VERSION 5.7 ;
  NOWIREEXTENSIONATPIN ON ;
  DIVIDERCHAR "/" ;
  BUSBITCHARS "[]" ;
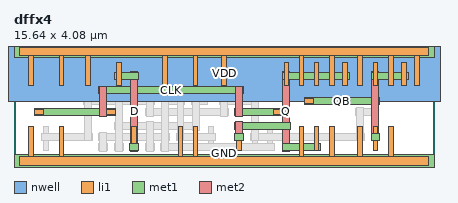
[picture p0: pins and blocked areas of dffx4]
MACRO dffx4
  CLASS BLOCK ;
  FOREIGN dffx4 ;
  ORIGIN 0.000 0.000 ;
  SIZE 15.640 BY 4.080 ;
  PIN VDD
    ANTENNADIFFAREA 7.371200 ;
    PORT
      LAYER nwell ;
        RECT -0.230 2.200 15.870 4.410 ;
      LAYER li1 ;
        RECT 0.210 3.915 15.430 4.245 ;
        RECT 0.545 2.800 0.715 3.915 ;
        RECT 1.685 2.800 1.855 3.915 ;
        RECT 2.665 2.800 2.835 3.915 ;
        RECT 5.545 2.800 5.715 3.915 ;
        RECT 6.675 2.800 6.845 3.915 ;
        RECT 7.735 2.800 7.905 3.915 ;
        RECT 10.615 2.800 10.785 3.915 ;
        RECT 11.755 2.800 11.925 3.915 ;
        RECT 12.805 2.800 12.975 3.915 ;
        RECT 13.945 2.800 14.115 3.915 ;
        RECT 14.925 2.800 15.095 3.915 ;
      LAYER met1 ;
        RECT 0.000 3.840 15.640 4.320 ;
    END
  END VDD
  PIN GND
    ANTENNADIFFAREA 6.346400 ;
    PORT
      LAYER li1 ;
        RECT 0.545 0.165 0.715 1.280 ;
        RECT 1.685 0.165 1.855 1.280 ;
        RECT 6.115 0.165 6.285 1.280 ;
        RECT 6.675 0.165 6.845 1.280 ;
        RECT 10.615 0.165 10.785 1.280 ;
        RECT 11.755 0.165 11.925 1.280 ;
        RECT 12.805 0.165 12.975 1.280 ;
        RECT 13.945 0.165 14.115 1.280 ;
        RECT 0.210 -0.165 15.430 0.165 ;
      LAYER met1 ;
        RECT 0.000 -0.240 15.640 0.240 ;
    END
  END GND
  PIN CLK
    ANTENNAGATEAREA 2.074800 ;
    PORT
      LAYER li1 ;
        RECT 0.750 1.745 1.080 1.915 ;
        RECT 3.445 1.745 3.775 1.915 ;
        RECT 9.675 1.745 10.005 1.915 ;
      LAYER met1 ;
        RECT 3.150 2.500 8.540 2.760 ;
        RECT 0.755 1.700 3.770 1.960 ;
        RECT 8.220 1.700 10.000 1.960 ;
      LAYER met2 ;
        RECT 3.180 1.670 3.440 2.790 ;
        RECT 8.250 1.670 8.510 2.790 ;
    END
  END CLK
  PIN D
    ANTENNADIFFAREA 0.621600 ;
    PORT
      LAYER li1 ;
        RECT 3.825 2.800 3.995 3.680 ;
        RECT 4.385 0.400 4.555 1.280 ;
      LAYER met1 ;
        RECT 3.750 3.040 4.630 3.300 ;
        RECT 4.310 0.380 4.630 0.640 ;
      LAYER met2 ;
        RECT 4.340 0.350 4.600 3.330 ;
    END
  END D
  PIN Q
    ANTENNADIFFAREA 1.161300 ;
    PORT
      LAYER li1 ;
        RECT 10.055 2.800 10.225 3.680 ;
        RECT 11.185 2.800 11.355 3.680 ;
        RECT 12.245 2.800 12.415 3.680 ;
        RECT 8.295 0.400 8.465 0.995 ;
        RECT 11.185 0.400 11.355 1.280 ;
      LAYER met1 ;
        RECT 9.980 3.040 12.490 3.300 ;
        RECT 8.220 1.180 10.300 1.440 ;
        RECT 8.220 0.780 8.540 1.040 ;
        RECT 9.980 0.380 11.430 0.640 ;
      LAYER met2 ;
        RECT 8.250 0.750 8.510 1.470 ;
        RECT 10.010 0.350 10.270 3.330 ;
    END
  END Q
  PIN QB
    ANTENNAGATEAREA 1.192800 ;
    ANTENNADIFFAREA 0.772800 ;
    PORT
      LAYER li1 ;
        RECT 13.375 2.800 13.545 3.680 ;
        RECT 14.435 2.800 14.605 3.680 ;
        RECT 10.820 2.145 11.150 2.315 ;
        RECT 13.375 0.400 13.545 1.280 ;
      LAYER met1 ;
        RECT 13.300 3.040 14.680 3.300 ;
        RECT 10.825 2.100 13.620 2.360 ;
        RECT 13.300 0.780 13.620 1.040 ;
      LAYER met2 ;
        RECT 13.330 0.750 13.590 3.330 ;
    END
  END QB
  OBS
      LAYER li1 ;
        RECT 1.115 2.800 1.285 3.680 ;
        RECT 2.175 2.800 2.345 3.680 ;
        RECT 3.225 2.800 3.395 3.680 ;
        RECT 4.385 2.800 4.555 3.680 ;
        RECT 4.985 2.800 5.155 3.680 ;
        RECT 6.115 2.800 6.285 3.680 ;
        RECT 7.245 2.800 7.415 3.680 ;
        RECT 8.295 2.800 8.465 3.680 ;
        RECT 8.895 2.800 9.065 3.680 ;
        RECT 9.455 2.800 9.625 3.680 ;
        RECT 4.605 2.145 4.935 2.315 ;
        RECT 5.750 2.145 6.080 2.315 ;
        RECT 6.880 2.145 7.210 2.315 ;
        RECT 8.515 2.145 8.845 2.315 ;
        RECT 13.010 1.745 13.340 1.915 ;
        RECT 1.115 0.400 1.285 1.280 ;
        RECT 3.225 0.400 3.395 0.860 ;
        RECT 3.825 0.400 3.995 0.860 ;
        RECT 4.985 0.400 5.155 1.280 ;
        RECT 5.545 0.400 5.715 1.280 ;
        RECT 7.245 0.400 7.415 1.280 ;
        RECT 8.895 0.400 9.065 0.995 ;
        RECT 9.455 0.400 9.625 1.280 ;
        RECT 10.055 0.400 10.225 1.280 ;
      LAYER met1 ;
        RECT 3.150 3.440 4.630 3.700 ;
        RECT 5.470 3.440 9.140 3.700 ;
        RECT 1.040 3.040 2.910 3.300 ;
        RECT 4.910 3.040 5.790 3.300 ;
        RECT 6.040 3.040 7.490 3.300 ;
        RECT 8.220 3.040 9.700 3.300 ;
        RECT 2.590 2.100 5.230 2.360 ;
        RECT 5.755 2.100 6.360 2.360 ;
        RECT 6.600 2.100 7.205 2.360 ;
        RECT 7.660 2.100 8.840 2.360 ;
        RECT 4.910 1.700 7.980 1.960 ;
        RECT 12.730 1.700 13.335 1.960 ;
        RECT 3.750 1.180 6.920 1.440 ;
        RECT 1.040 0.780 2.910 1.040 ;
        RECT 3.150 0.780 5.790 1.040 ;
        RECT 6.040 0.780 7.490 1.040 ;
        RECT 8.820 0.780 13.050 1.040 ;
        RECT 3.150 0.380 3.470 0.640 ;
        RECT 3.750 0.380 4.070 0.640 ;
        RECT 4.910 0.380 5.230 0.640 ;
        RECT 5.470 0.380 9.700 0.640 ;
      LAYER met2 ;
        RECT 2.620 0.750 2.880 3.330 ;
        RECT 3.180 0.350 3.440 1.070 ;
        RECT 3.780 0.350 4.040 3.730 ;
        RECT 4.940 1.670 5.200 2.390 ;
        RECT 4.940 0.350 5.200 1.470 ;
        RECT 5.500 0.350 5.760 3.730 ;
        RECT 6.070 0.750 6.330 3.330 ;
        RECT 6.630 1.150 6.890 2.390 ;
        RECT 7.690 1.670 7.950 2.390 ;
        RECT 8.850 0.750 9.110 3.330 ;
        RECT 12.760 0.750 13.020 1.990 ;
  END
END dffx4
END LIBRARY

